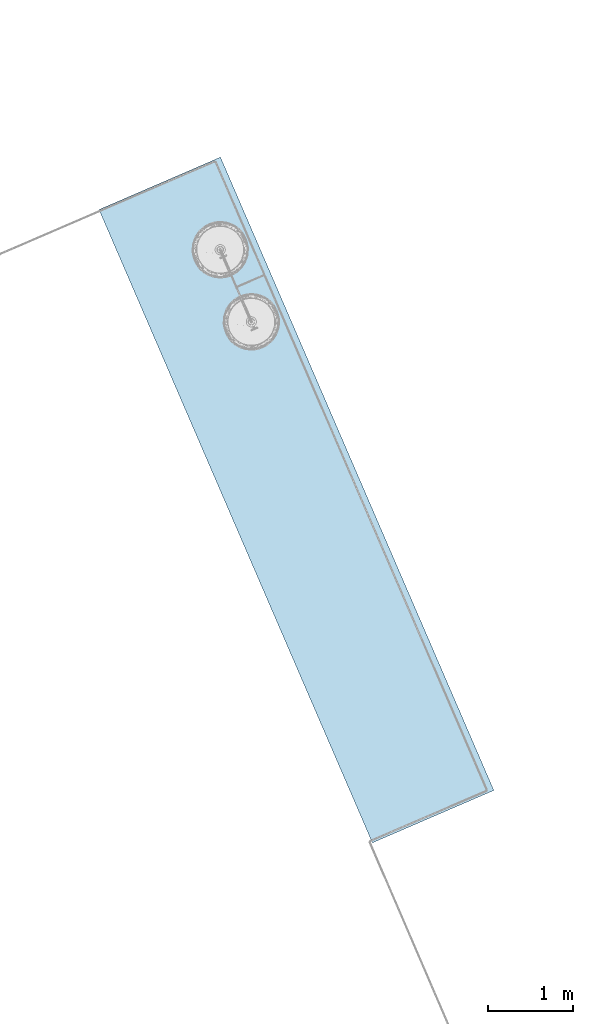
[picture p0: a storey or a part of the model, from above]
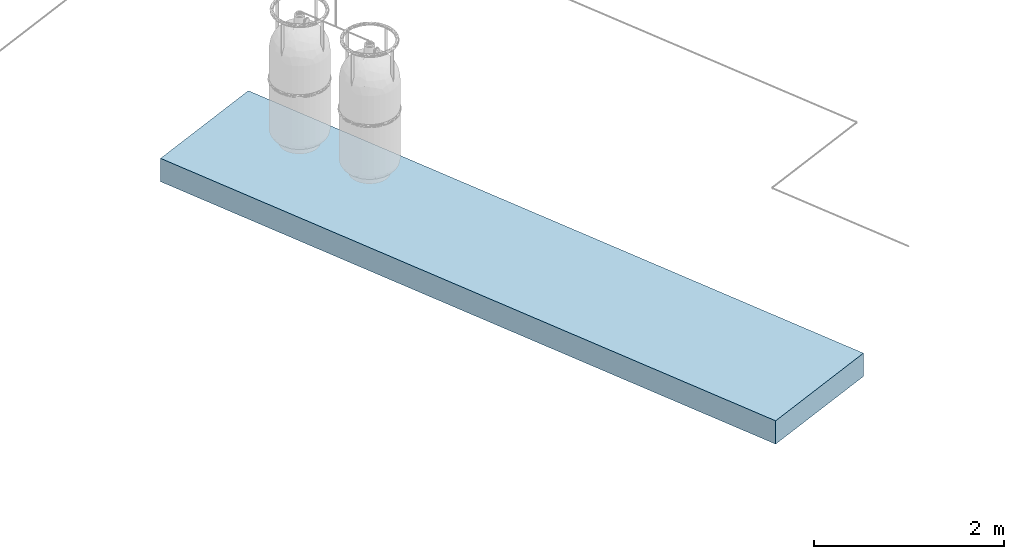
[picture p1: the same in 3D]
Properties of the parts of a building model (IFC4)

# File
Description: ViewDefinition [ReferenceView_V1.2], RevitIdentifiers [ContentGUID: 69321ab7-637c-4371-81d2-1dd4d23b8160, VersionGUID: b3f584a1-fc3a-4438-8aa8-f4ca3887ae56, NumberOfSaves: 3], CoordinateReference [CoordinateBase: Shared Coordinates, ProjectSite: Interno]
File name: C:\Users\Joaquin\Dropbox\BuildingProjects\2024 - Construcción Cesfam Coyhaique Con Sar Adosado\2_Modelos\all_models_2025-1-24_23.4.48\CCY_COOR-CCY_GAS_Enriched.ifc
Time: 2025-10-28T00:40:49-03:00
Written by: IfcOpenShell 0.8.3-post1
Made in: Bonsai 0.8.3-post1

# IfcProject, 2016_03
LongName: CESFAM Coyhaique; Phase: 2

# IfcSite, Default
RefLatitude: 42, 12, 46, 804504; RefLongitude: -71, -2, 0, -602416; RefElevation: 0 m
Pset_SiteCommon - Reference: Project Information
Other - Category: Project Information; Client Name: Servicio de Salud de Aysén; Project Address: Calle 2, s/n. Lote 1C.; Project Issue Date: Marzo 2017; Project Name: CESFAM Coyhaique; Project Number: 2016_03; Project Status: 2
Identity Data - Author: Astudillo y Aparicio Asociados Ltda.; Organization Description: Arquitectura e ingeniería integrada; Organization Name: Astudillo y Aparicio Asociados Ltda.

# IfcBuilding
Pset_BuildingCommon - Reference: Project Information; NumberOfStoreys: 2
Pset_BuildingElementProxyCommon - Reference: Project Information; IsExternal: no
Pset_BuildingSystemCommon - Reference: Project Information
Other - Category: Project Information; Client Name: Servicio de Salud de Aysén; Project Address: Calle 2, s/n. Lote 1C.; Project Issue Date: Marzo 2017; Project Name: CESFAM Coyhaique; Project Number: 2016_03; Project Status: 2
Identity Data - Author: Astudillo y Aparicio Asociados Ltda.; Organization Description: Arquitectura e ingeniería integrada; Organization Name: Astudillo y Aparicio Asociados Ltda.

# IfcBuildingStorey: Level:Extremo inicial 8 mm (2)
Other - Category: Levels; Family: Level; Family and Type: Level: Extremo inicial 8 mm; Type: Extremo inicial 8 mm; Type Id: 305
Dimensions - Computation Height: 0 m
Identity Data - Structural: no; Building Story: yes
Other(Type) - Category: Levels; Family Name: Level
Constraints(Type) - Elevation Base: Survey Point
Graphics(Type) - Color: 0; Line Pattern: Centro; Line Weight: 1; Symbol: M_Extremo inicial de nivel - Círculo; Symbol at End 1 Default: no; Symbol at End 2 Default: yes
Identity Data(Type) - Type Name: Extremo inicial 8 mm
Name | LongName = Name | Elevation (m) | Constraints, Elevation (m)
Nivel 1 | Nivel 1 | 0 | 317.15
Nivel 2 | Nivel 2 | 4.25 | 321.4

# IfcBurner: Mechero:Mechero (5)
Type - Material: <Unnamed>
Type - Other - Category: Mechanical Equipment; Family Name: Mechero
Type - Constraints - Default Elevation: 0 m
Type - Dimensions - Entrada: 0.013 m
Type - Identity Data - Type Name: Mechero
Classification: D20 (FEMAP58); Group: Otros 1
Pset_BuildingElementProxyCommon - IsExternal: no; Reference: Mechero:Mechero
Pset_EnvironmentalImpactIndicators - Reference: Mechero:Mechero
Qto_BuildingElementProxyQuantities - NetSurfaceArea: 0.51635 m2; NetVolume: 0.00811626 m3
Other - Family: Mechero; Family and Type: Mechero: Mechero; Type: Mechero; Type Id: 1006093
Constraints - Elevation from Level: 0.75 m; Offset from Host: 0.75 m
Dimensions - Area: 0.258175 m2; Volume: 0.00811626 m3
Mechanical - System Classification: Other; System Name: Otros 1
Phasing - Phase Created: Nueva construcción
AboveGround - AboveGround: yes
Name (Mechero:Mechero:...) | In | Level | Host | Mark
1006108 | Nivel 1 | Nivel 1 | Level : Nivel 1
1006902 | Nivel 1 | Nivel 1 | Level : Nivel 1 | 12
1006960 | Nivel 1 | Nivel 1 | Level : Nivel 1 | 13
1008166 | Nivel 2 | Nivel 2 | Level : Nivel 2 | 14
1008171 | Nivel 2 | Nivel 2 | Level : Nivel 2 | 15

# IfcDistributionPort (210)
Description: Flow; PredefinedType: PIPE
Name | FlowDirection | SystemType | Group
InPort_955634_1 | SINK | DOMESTICCOLDWATER
InPort_955634_2 | SINK | DOMESTICHOTWATER
InPort_955634_3 | SINK | SEWAGE
InPort_955636_1 | SINK | DOMESTICCOLDWATER
InPort_955636_2 | SINK | DOMESTICHOTWATER
InPort_955636_3 | SINK | SEWAGE
OutPort_996003_1 | SOURCE
Port_1001599_1 | SOURCEANDSINK
InPort_1008911_0 | SINK | USERDEFINED | Otros 2
OutPort_1001599_2 | SOURCE | USERDEFINED | Otros 2
InPort_1007986_1 | SINK | USERDEFINED | Otros 1
OutPort_1003499_1 | SOURCE | USERDEFINED | Otros 1
InPort_1007988_1 | SINK | USERDEFINED | Otros 1
OutPort_1004430_1 | SOURCE | USERDEFINED | Otros 1
InPort_1007066_2 | SINK | USERDEFINED | Otros 1
OutPort_1006108_1 | SOURCE | USERDEFINED | Otros 1
InPort_1007020_1 | SINK | USERDEFINED | Otros 1
OutPort_1006902_1 | SOURCE | USERDEFINED | Otros 1
InPort_1006984_1 | SINK | USERDEFINED | Otros 1
OutPort_1006960_1 | SOURCE | USERDEFINED | Otros 1
Port_1006974_0 | SOURCEANDSINK | USERDEFINED | Otros 1
Port_1006984_2 | SOURCEANDSINK | USERDEFINED | Otros 1
Port_1006974_1 | SOURCEANDSINK | USERDEFINED | Otros 1
Port_1007147_2 | SOURCEANDSINK | USERDEFINED | Otros 1
Port_1006987_0 | SOURCEANDSINK | USERDEFINED | Otros 1
Port_1007676_2 | SOURCEANDSINK | USERDEFINED | Otros 1
Port_1006987_1 | SOURCEANDSINK | USERDEFINED | Otros 1
Port_1007147_1 | SOURCEANDSINK | USERDEFINED | Otros 1
Port_1007012_0 | SOURCEANDSINK | USERDEFINED | Otros 1
Port_1007020_2 | SOURCEANDSINK | USERDEFINED | Otros 1
Port_1007012_1 | SOURCEANDSINK | USERDEFINED | Otros 1
Port_1007030_1 | SOURCEANDSINK | USERDEFINED | Otros 1
Port_1007022_0 | SOURCEANDSINK | USERDEFINED | Otros 1
Port_1007062_1 | SOURCEANDSINK | USERDEFINED | Otros 1
Port_1007022_1 | SOURCEANDSINK | USERDEFINED | Otros 1
Port_1008821_1 | SOURCEANDSINK | USERDEFINED | Otros 1
Port_1007030_2 | SOURCEANDSINK | USERDEFINED | Otros 1
Port_1007063_0 | SOURCEANDSINK | USERDEFINED | Otros 1
Port_1007050_0 | SOURCEANDSINK | USERDEFINED | Otros 1
Port_1007062_3 | SOURCEANDSINK | USERDEFINED | Otros 1
Port_1007050_1 | SOURCEANDSINK | USERDEFINED | Otros 1
Port_1007066_1 | SOURCEANDSINK | USERDEFINED | Otros 1
Port_1007062_2 | SOURCEANDSINK | USERDEFINED | Otros 1
Port_1007063_1 | SOURCEANDSINK | USERDEFINED | Otros 1
Port_1007094_0 | SOURCEANDSINK | USERDEFINED | Otros 1
Port_1008833_2 | SOURCEANDSINK | USERDEFINED | Otros 1
Port_1007094_1 | SOURCEANDSINK | USERDEFINED | Otros 1
Port_1007117_1 | SOURCEANDSINK | USERDEFINED | Otros 1
Port_1007111_0 | SOURCEANDSINK | USERDEFINED | Otros 1
Port_1008793_1 | SOURCEANDSINK | USERDEFINED | Otros 1
Port_1007111_1 | SOURCEANDSINK | USERDEFINED | Otros 1
Port_1008694_1 | SOURCEANDSINK | USERDEFINED | Otros 1
Port_1007117_2 | SOURCEANDSINK | USERDEFINED | Otros 1
Port_1008794_0 | SOURCEANDSINK | USERDEFINED | Otros 1
Port_1007164_0 | SOURCEANDSINK | USERDEFINED | Otros 1
Port_1007988_2 | SOURCEANDSINK | USERDEFINED | Otros 1
Port_1007164_1 | SOURCEANDSINK | USERDEFINED | Otros 1
Port_1007992_2 | SOURCEANDSINK | USERDEFINED | Otros 1
Port_1007174_0 | SOURCEANDSINK | USERDEFINED | Otros 1
Port_1007986_2 | SOURCEANDSINK | USERDEFINED | Otros 1
Port_1007174_1 | SOURCEANDSINK | USERDEFINED | Otros 1
Port_1007990_2 | SOURCEANDSINK | USERDEFINED | Otros 1
Port_1007210_0 | SOURCEANDSINK | USERDEFINED | Otros 1
Port_1008692_1 | SOURCEANDSINK | USERDEFINED | Otros 1
Port_1007210_1 | SOURCEANDSINK | USERDEFINED | Otros 1
Port_1008043_1 | SOURCEANDSINK | USERDEFINED | Otros 1
Port_1007220_0 | SOURCEANDSINK | USERDEFINED | Otros 1
Port_1007467_2 | SOURCEANDSINK | USERDEFINED | Otros 1
Port_1007220_1 | SOURCEANDSINK | USERDEFINED | Otros 1
Port_1008043_3 | SOURCEANDSINK | USERDEFINED | Otros 1
Port_1007234_0 | SOURCEANDSINK | USERDEFINED | Otros 1
Port_1007463_1 | SOURCEANDSINK | USERDEFINED | Otros 1
Port_1007234_1 | SOURCEANDSINK | USERDEFINED | Otros 1
Port_1007266_2 | SOURCEANDSINK | USERDEFINED | Otros 1
Port_1007260_1 | SOURCEANDSINK | USERDEFINED | Otros 1
Port_1007990_1 | SOURCEANDSINK | USERDEFINED | Otros 1
Port_1007260_2 | SOURCEANDSINK | USERDEFINED | Otros 1
Port_1007262_1 | SOURCEANDSINK | USERDEFINED | Otros 1
Port_1007262_2 | SOURCEANDSINK | USERDEFINED | Otros 1
Port_1007464_0 | SOURCEANDSINK | USERDEFINED | Otros 1
Port_1007264_1 | SOURCEANDSINK | USERDEFINED | Otros 1
Port_1007992_1 | SOURCEANDSINK | USERDEFINED | Otros 1
Port_1007264_2 | SOURCEANDSINK | USERDEFINED | Otros 1
Port_1007266_1 | SOURCEANDSINK | USERDEFINED | Otros 1
Port_1007461_0 | SOURCEANDSINK | USERDEFINED | Otros 1
Port_1007463_3 | SOURCEANDSINK | USERDEFINED | Otros 1
Port_1007461_1 | SOURCEANDSINK | USERDEFINED | Otros 1
Port_1007467_1 | SOURCEANDSINK | USERDEFINED | Otros 1
Port_1007463_2 | SOURCEANDSINK | USERDEFINED | Otros 1
Port_1007464_1 | SOURCEANDSINK | USERDEFINED | Otros 1
Port_1007626_0 | SOURCEANDSINK | USERDEFINED | Otros 1
Port_1007674_2 | SOURCEANDSINK | USERDEFINED | Otros 1
Port_1007626_1 | SOURCEANDSINK | USERDEFINED | Otros 1
Port_1008785_1 | SOURCEANDSINK | USERDEFINED | Otros 1
Port_1007649_0 | SOURCEANDSINK | USERDEFINED | Otros 1
Port_1007674_1 | SOURCEANDSINK | USERDEFINED | Otros 1
Port_1007649_1 | SOURCEANDSINK | USERDEFINED | Otros 1
Port_1007676_1 | SOURCEANDSINK | USERDEFINED | Otros 1
Port_1008043_2 | SOURCEANDSINK | USERDEFINED | Otros 1
Port_1008054_0 | SOURCEANDSINK | USERDEFINED | Otros 1
Port_1008054_1 | SOURCEANDSINK | USERDEFINED | Otros 1
Port_1008076_2 | SOURCEANDSINK | USERDEFINED | Otros 1
Port_1008068_0 | SOURCEANDSINK | USERDEFINED | Otros 1
Port_1008076_1 | SOURCEANDSINK | USERDEFINED | Otros 1
Port_1008068_1 | SOURCEANDSINK | USERDEFINED | Otros 1
Port_1008084_1 | SOURCEANDSINK | USERDEFINED | Otros 1
Port_1008078_0 | SOURCEANDSINK | USERDEFINED | Otros 1
Port_1008084_2 | SOURCEANDSINK | USERDEFINED | Otros 1
Port_1008078_1 | SOURCEANDSINK | USERDEFINED | Otros 1
Port_1008590_1 | SOURCEANDSINK | USERDEFINED | Otros 1
InPort_1008327_2 | SINK | USERDEFINED | Otros 1
OutPort_1008166_1 | SOURCE | USERDEFINED | Otros 1
InPort_1008290_1 | SINK | USERDEFINED | Otros 1
OutPort_1008171_1 | SOURCE | USERDEFINED | Otros 1
Port_1008210_0 | SOURCEANDSINK | USERDEFINED | Otros 1
Port_1008590_2 | SOURCEANDSINK | USERDEFINED | Otros 1
Port_1008210_1 | SOURCEANDSINK | USERDEFINED | Otros 1
Port_1008592_2 | SOURCEANDSINK | USERDEFINED | Otros 1
Port_1008239_0 | SOURCEANDSINK | USERDEFINED | Otros 1
Port_1008395_1 | SOURCEANDSINK | USERDEFINED | Otros 1
Port_1008239_1 | SOURCEANDSINK | USERDEFINED | Otros 1
Port_1008592_1 | SOURCEANDSINK | USERDEFINED | Otros 1
Port_1008275_0 | SOURCEANDSINK | USERDEFINED | Otros 1
Port_1008290_2 | SOURCEANDSINK | USERDEFINED | Otros 1
Port_1008275_1 | SOURCEANDSINK | USERDEFINED | Otros 1
Port_1008298_1 | SOURCEANDSINK | USERDEFINED | Otros 1
Port_1008292_0 | SOURCEANDSINK | USERDEFINED | Otros 1
Port_1008323_1 | SOURCEANDSINK | USERDEFINED | Otros 1
Port_1008292_1 | SOURCEANDSINK | USERDEFINED | Otros 1
Port_1008395_2 | SOURCEANDSINK | USERDEFINED | Otros 1
Port_1008298_2 | SOURCEANDSINK | USERDEFINED | Otros 1
Port_1008324_0 | SOURCEANDSINK | USERDEFINED | Otros 1
Port_1008311_0 | SOURCEANDSINK | USERDEFINED | Otros 1
Port_1008323_3 | SOURCEANDSINK | USERDEFINED | Otros 1
Port_1008311_1 | SOURCEANDSINK | USERDEFINED | Otros 1
Port_1008327_1 | SOURCEANDSINK | USERDEFINED | Otros 1
Port_1008323_2 | SOURCEANDSINK | USERDEFINED | Otros 1
Port_1008324_1 | SOURCEANDSINK | USERDEFINED | Otros 1
Port_1008690_0 | SOURCEANDSINK | USERDEFINED | Otros 1
Port_1008692_2 | SOURCEANDSINK | USERDEFINED | Otros 1
Port_1008690_1 | SOURCEANDSINK | USERDEFINED | Otros 1
Port_1008694_2 | SOURCEANDSINK | USERDEFINED | Otros 1
Port_1008774_0 | SOURCEANDSINK | USERDEFINED | Otros 1
Port_1008793_3 | SOURCEANDSINK | USERDEFINED | Otros 1
Port_1008774_1 | SOURCEANDSINK | USERDEFINED | Otros 1
Port_1008797_2 | SOURCEANDSINK | USERDEFINED | Otros 1
Port_1008783_0 | SOURCEANDSINK | USERDEFINED | Otros 1
Port_1008785_2 | SOURCEANDSINK | USERDEFINED | Otros 1
Port_1008783_1 | SOURCEANDSINK | USERDEFINED | Otros 1
Port_1008797_1 | SOURCEANDSINK | USERDEFINED | Otros 1
Port_1008793_2 | SOURCEANDSINK | USERDEFINED | Otros 1
Port_1008794_1 | SOURCEANDSINK | USERDEFINED | Otros 1
Port_1008808_0 | SOURCEANDSINK | USERDEFINED | Otros 1
Port_1008833_1 | SOURCEANDSINK | USERDEFINED | Otros 1
Port_1008808_1 | SOURCEANDSINK | USERDEFINED | Otros 1
Port_1008835_2 | SOURCEANDSINK | USERDEFINED | Otros 1
Port_1008819_0 | SOURCEANDSINK | USERDEFINED | Otros 1
Port_1008821_2 | SOURCEANDSINK | USERDEFINED | Otros 1
Port_1008819_1 | SOURCEANDSINK | USERDEFINED | Otros 1
Port_1008835_1 | SOURCEANDSINK | USERDEFINED | Otros 1
Port_1008885_1 | SOURCEANDSINK
InPort_1009899_0 | SINK | USERDEFINED | Otros 2
OutPort_1008885_2 | SOURCE | USERDEFINED | Otros 2
Port_1008899_0 | SOURCEANDSINK | USERDEFINED | Otros 2
Port_1008913_2 | SOURCEANDSINK | USERDEFINED | Otros 2
Port_1008899_1 | SOURCEANDSINK | USERDEFINED | Otros 2
Port_1008951_1 | SOURCEANDSINK | USERDEFINED | Otros 2
Port_1008911_1 | SOURCEANDSINK | USERDEFINED | Otros 2
Port_1008913_1 | SOURCEANDSINK | USERDEFINED | Otros 2
Port_1008951_2 | SOURCEANDSINK | USERDEFINED | Otros 2
Port_1009927_0 | SOURCEANDSINK | USERDEFINED | Otros 2
Port_1009399_0 | SOURCEANDSINK | USERDEFINED | Otros 2
Port_1009926_1 | SOURCEANDSINK | USERDEFINED | Otros 2
Port_1009399_1 | SOURCEANDSINK | USERDEFINED | Otros 2
Port_1009435_1 | SOURCEANDSINK | USERDEFINED | Otros 2
Port_1009425_0 | SOURCEANDSINK | USERDEFINED | Otros 2
Port_1009435_2 | SOURCEANDSINK | USERDEFINED | Otros 2
Port_1009425_1 | SOURCEANDSINK | USERDEFINED | Otros 2
Port_1009476_1 | SOURCEANDSINK | USERDEFINED | Otros 2
Port_1009437_0 | SOURCEANDSINK | USERDEFINED | Otros 2
Port_1009478_2 | SOURCEANDSINK | USERDEFINED | Otros 2
Port_1009437_1 | SOURCEANDSINK | USERDEFINED | Otros 2
Port_1009531_1 | SOURCEANDSINK | USERDEFINED | Otros 2
Port_1009474_0 | SOURCEANDSINK | USERDEFINED | Otros 2
Port_1009476_2 | SOURCEANDSINK | USERDEFINED | Otros 2
Port_1009474_1 | SOURCEANDSINK | USERDEFINED | Otros 2
Port_1009478_1 | SOURCEANDSINK | USERDEFINED | Otros 2
Port_1009482_0 | SOURCEANDSINK | USERDEFINED | Otros 2
Port_1009535_2 | SOURCEANDSINK | USERDEFINED | Otros 2
Port_1009482_1 | SOURCEANDSINK | USERDEFINED | Otros 2
Port_1009799_1 | SOURCEANDSINK | USERDEFINED | Otros 2
Port_1009529_0 | SOURCEANDSINK | USERDEFINED | Otros 2
Port_1009531_2 | SOURCEANDSINK | USERDEFINED | Otros 2
Port_1009529_1 | SOURCEANDSINK | USERDEFINED | Otros 2
Port_1009535_1 | SOURCEANDSINK | USERDEFINED | Otros 2
Port_1009539_0 | SOURCEANDSINK | USERDEFINED | Otros 2
Port_1009799_2 | SOURCEANDSINK | USERDEFINED | Otros 2
Port_1009539_1 | SOURCEANDSINK | USERDEFINED | Otros 2
Port_1009810_1 | SOURCEANDSINK | USERDEFINED | Otros 2
Port_1009802_0 | SOURCEANDSINK | USERDEFINED | Otros 2
Port_1009810_2 | SOURCEANDSINK | USERDEFINED | Otros 2
Port_1009802_1 | SOURCEANDSINK | USERDEFINED | Otros 2
Port_1009889_0 | SOURCEANDSINK | USERDEFINED | Otros 2
Port_1009926_3 | SOURCEANDSINK | USERDEFINED | Otros 2
Port_1009889_1 | SOURCEANDSINK | USERDEFINED | Otros 2
Port_1009930_2 | SOURCEANDSINK | USERDEFINED | Otros 2
Port_1009899_1 | SOURCEANDSINK | USERDEFINED | Otros 2
Port_1009930_1 | SOURCEANDSINK | USERDEFINED | Otros 2
Port_1009926_2 | SOURCEANDSINK | USERDEFINED | Otros 2
Port_1009927_1 | SOURCEANDSINK | USERDEFINED | Otros 2

# IfcDistributionSystem: Otros (2)
PredefinedType: USERDEFINED
Pset_DistributionSystemCommon - Reference: Piping System:Otros
Name
Otros 2
Otros 1

# IfcFlowTerminal: M_Fregadero - Isla - Simple:455 mm x 455 mm - Público (2)
In: Nivel 1
Type - Material: <Unnamed>
Type - Other - Category: Plumbing Fixtures; Family Name: M_Fregadero - Isla - Simple
Type - Constraints - Default Elevation: 0 m
Type - Dimensions - Anchura de fregadero: 0.455 m; Diámetro de agua caliente: 0.015 m; Diámetro de agua fría: 0.015 m; Diámetro de sanitario: 0.04 m; Longitud de fregadero: 0.455 m; Profundidad de fregadero: 0.203 m; Radio de agua caliente: 0.0075 m; Radio de agua fría: 0.0075 m; Radio de sanitario: 0.02 m
Type - Identity Data - OmniClass Number: 23.45.05.14.14; OmniClass Title: Sinks/Lavatories; Type Name: 455 mm x 455 mm - Público
Type - Mechanical - CWFU: 3; HWFU: 3; WFU: 2
Classification: D20 (FEMAP58)
Pset_EnvironmentalImpactIndicators - Reference: M_Fregadero - Isla - Simple:455 mm x 455 mm - Público
Other - Family: M_Fregadero - Isla - Simple; Family and Type: M_Fregadero - Isla - Simple: 455 mm x 455 mm - Público; Type: 455 mm x 455 mm - Público; Type Id: 921487
Constraints - Elevation from Level: 0 m
Dimensions - Area: 0.498697 m2; Volume: 0.00640577 m3
Mechanical - System Classification: Domestic Cold Water,Domestic Hot Water,Sanitary
Phasing - Phase Created: Nueva construcción
Plumbing - Presión de flujo: 55158 Pa
AboveGround - AboveGround: yes
Name (M_Fregadero - Isla - Simple:455 mm x 455 mm - Público:...) | Mark
955634 | 228
955636 | 230

# IfcGrid (2)
AboveGround - AboveGround: yes
Name | In
Default Grid | Nivel 1
Default Grid | Nivel 2

# IfcPipeFitting: M_Codo - Genérico:Norma (31)
Type - Material: <Unnamed>
Type - Other - Category: Pipe Fittings; Family Name: M_Codo - Genérico; Nombre de tabla de consulta: M_Pipe Fitting - Generic
Type - Constraints - Default Elevation: 0 m
Type - Identity Data - OmniClass Number: 23.60.30.11.14; OmniClass Title: Pipework Fittings; Type Name: Norma
Type - Mechanical - Loss Method: K Coefficient from Table; Connection Type: Generic; K Coefficient Table: Regular 45, 90 and 180 Elbow
Classification: D20 (FEMAP58)
Pset_EnvironmentalImpactIndicators - Reference: M_Codo - Genérico:Norma; sets with these values: 2
Other - Type: Norma; Family: M_Codo - Genérico; Family and Type: M_Codo - Genérico: Norma; Type Id: 133158
Dimensions - Ángulo: 90 deg
Graphics - Use Annotation Scale: yes
Mechanical - System Type: Otros; System Classification: Other
Phasing - Phase Created: Nueva construcción
Insulation - Insulation Thickness: 0 m
AboveGround - AboveGround: yes
Name (M_Codo - Genérico:Norma:...) | In | Radio central (m) = Centro a extremo (m) | Radio exterior de unión (m) | Level | Elevation from Level (m) | Diámetro exterior de unión (m) | Diámetro nominal (m) = Maximum Size (m) = Minimum Size (m) | Radio nominal (m) | Size | Tamaño de marca (m) | Volume (m3) | System Name = Group | Overall Size
1007030 | Nivel 1 | 0.0174625 | 0.0111125 | Nivel 1 | 0.8555 | 0.022225 | 0.02 | 0.01 | 0.020ø-0.020ø | 0.00889 | 0.0000106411 | Otros 1 | 20 mmø-20 mmø
1007117 | Nivel 1 | 0.0174625 | 0.0111125 | Nivel 1 | 3 | 0.022225 | 0.02 | 0.01 | 0.020ø-0.020ø | 0.00889 | 0.0000106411 | Otros 1 | 20 mmø-20 mmø
1007147 | Nivel 1 | 0.0174625 | 0.0111125 | Nivel 1 | 0.8555 | 0.022225 | 0.02 | 0.01 | 0.020ø-0.020ø | 0.00889 | 0.0000106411 | Otros 1 | 20 mmø-20 mmø
1007260 | Nivel 1 | 0.0144375 | 0.0080875 | Nivel 1 | 1.6819 | 0.016175 | 0.013 | 0.0065 | 0.013ø-0.013ø | 0.00647 | 0.00000465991 | Otros 1 | 13 mmø-13 mmø
1007264 | Nivel 1 | 0.0144375 | 0.0080875 | Nivel 1 | 1.6819 | 0.016175 | 0.013 | 0.0065 | 0.013ø-0.013ø | 0.00647 | 0.00000465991 | Otros 1 | 13 mmø-13 mmø
1007467 | Nivel 1 | 0.0174625 | 0.0111125 | Nivel 1 | 3 | 0.022225 | 0.02 | 0.01 | 0.020ø-0.020ø | 0.00889 | 0.0000106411 | Otros 1 | 20 mmø-20 mmø | Identity Data - Comments: GAS
1007674 | Nivel 1 | 0.0174625 | 0.0111125 | Nivel 1 | 0.8555 | 0.022225 | 0.02 | 0.01 | 0.020ø-0.020ø | 0.00889 | 0.0000106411 | Otros 1 | 20 mmø-20 mmø
1007676 | Nivel 1 | 0.0174625 | 0.0111125 | Nivel 1 | 0.8555 | 0.022225 | 0.02 | 0.01 | 0.020ø-0.020ø | 0.00889 | 0.0000106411 | Otros 1 | 20 mmø-20 mmø
1008076 | Nivel 1 | 0.0174625 | 0.0111125 | Nivel 1 | 3 | 0.022225 | 0.02 | 0.01 | 0.020ø-0.020ø | 0.00889 | 0.0000106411 | Otros 1 | 20 mmø-20 mmø
1008084 | Nivel 1 | 0.0174625 | 0.0111125 | Nivel 1 | 3 | 0.022225 | 0.02 | 0.01 | 0.020ø-0.020ø | 0.00889 | 0.0000106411 | Otros 1 | 20 mmø-20 mmø
1008298 | Nivel 2 | 0.0174625 | 0.0111125 | Nivel 2 | 0.8555 | 0.022225 | 0.02 | 0.01 | 0.020ø-0.020ø | 0.00889 | 0.0000106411 | Otros 1 | 20 mmø-20 mmø
1008395 | Nivel 1 | 0.0174625 | 0.0111125 | Nivel 1 | 5.1055 | 0.022225 | 0.02 | 0.01 | 0.020ø-0.020ø | 0.00889 | 0.0000106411 | Otros 1 | 20 mmø-20 mmø
1008590 | Nivel 1 | 0.0174625 | 0.0111125 | Nivel 1 | 3 | 0.022225 | 0.02 | 0.01 | 0.020ø-0.020ø | 0.00889 | 0.0000106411 | Otros 1 | 20 mmø-20 mmø
1008592 | Nivel 1 | 0.0174625 | 0.0111125 | Nivel 1 | 3 | 0.022225 | 0.02 | 0.01 | 0.020ø-0.020ø | 0.00889 | 0.0000106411 | Otros 1 | 20 mmø-20 mmø
1008692 | Nivel 1 | 0.0174625 | 0.0111125 | Nivel 1 | 3 | 0.022225 | 0.02 | 0.01 | 0.020ø-0.020ø | 0.00889 | 0.0000106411 | Otros 1 | 20 mmø-20 mmø | Identity Data - Comments: GAS
1008694 | Nivel 1 | 0.0174625 | 0.0111125 | Nivel 1 | 3 | 0.022225 | 0.02 | 0.01 | 0.020ø-0.020ø | 0.00889 | 0.0000106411 | Otros 1 | 20 mmø-20 mmø | Identity Data - Comments: GAS
1008785 | Nivel 1 | 0.0174625 | 0.0111125 | Nivel 1 | 0.8555 | 0.022225 | 0.02 | 0.01 | 0.020ø-0.020ø | 0.00889 | 0.0000106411 | Otros 1 | 20 mmø-20 mmø
1008797 | Nivel 1 | 0.0174625 | 0.0111125 | Nivel 1 | 3 | 0.022225 | 0.02 | 0.01 | 0.020ø-0.020ø | 0.00889 | 0.0000106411 | Otros 1 | 20 mmø-20 mmø
1008821 | Nivel 1 | 0.0174625 | 0.0111125 | Nivel 1 | 0.8555 | 0.022225 | 0.02 | 0.01 | 0.020ø-0.020ø | 0.00889 | 0.0000106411 | Otros 1 | 20 mmø-20 mmø
1008833 | Nivel 1 | 0.0174625 | 0.0111125 | Nivel 1 | 3 | 0.022225 | 0.02 | 0.01 | 0.020ø-0.020ø | 0.00889 | 0.0000106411 | Otros 1 | 20 mmø-20 mmø
1008835 | Nivel 1 | 0.0174625 | 0.0111125 | Nivel 1 | 3 | 0.022225 | 0.02 | 0.01 | 0.020ø-0.020ø | 0.00889 | 0.0000106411 | Otros 1 | 20 mmø-20 mmø | Mechanical - Flow - Pressure Drop: 0 Pa
1008913 | Nivel 1 | 0.0206375 | 0.0142875 | Nivel 1 | -0.44 | 0.028575 | 0.025 | 0.0125 | 0.025ø-0.025ø | 0.01143 | 0.0000207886 | Otros 2 | 25 mmø-25 mmø
1008951 | Nivel 1 | 0.0206375 | 0.0142875 | Nivel 1 | -0.44 | 0.028575 | 0.025 | 0.0125 | 0.025ø-0.025ø | 0.01143 | 0.0000207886 | Otros 2 | 25 mmø-25 mmø
1009435 | Nivel 1 | 0.0206375 | 0.0142875 | Nivel 1 | -0.44 | 0.028575 | 0.025 | 0.0125 | 0.025ø-0.025ø | 0.01143 | 0.0000207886 | Otros 2 | 25 mmø-25 mmø
1009476 | Nivel 1 | 0.0206375 | 0.0142875 | Nivel 1 | -0.44 | 0.028575 | 0.025 | 0.0125 | 0.025ø-0.025ø | 0.01143 | 0.0000207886 | Otros 2 | 25 mmø-25 mmø
1009478 | Nivel 1 | 0.0206375 | 0.0142875 | Nivel 1 | 0.4 | 0.028575 | 0.025 | 0.0125 | 0.025ø-0.025ø | 0.01143 | 0.0000207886 | Otros 2 | 25 mmø-25 mmø
1009531 | Nivel 1 | 0.0206375 | 0.0142875 | Nivel 1 | 0.4 | 0.028575 | 0.025 | 0.0125 | 0.025ø-0.025ø | 0.01143 | 0.0000207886 | Otros 2 | 25 mmø-25 mmø
1009535 | Nivel 1 | 0.0206375 | 0.0142875 | Nivel 1 | 1.8 | 0.028575 | 0.025 | 0.0125 | 0.025ø-0.025ø | 0.01143 | 0.0000207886 | Otros 2 | 25 mmø-25 mmø
1009799 | Nivel 1 | 0.0206375 | 0.0142875 | Nivel 1 | 1.8 | 0.028575 | 0.025 | 0.0125 | 0.025ø-0.025ø | 0.01143 | 0.0000207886 | Otros 2 | 25 mmø-25 mmø
1009810 | Nivel 1 | 0.0206375 | 0.0142875 | Nivel 1 | 3.84207 | 0.028575 | 0.025 | 0.0125 | 0.025ø-0.025ø | 0.01143 | 0.0000207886 | Otros 2 | 25 mmø-25 mmø
1009930 | Nivel 1 | 0.0206375 | 0.0142875 | Nivel 1 | -0.44 | 0.028575 | 0.025 | 0.0125 | 0.025ø-0.025ø | 0.01143 | 0.0000207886 | Otros 2 | 25 mmø-25 mmø

# IfcPipeFitting: M_Te - Genérica:Norma (6)
Type - Material: <Unnamed>
Type - Other - Category: Pipe Fittings; Family Name: M_Te - Genérica; Nombre de tabla de consulta: M_Pipe Fitting - Generic
Type - Constraints - Default Elevation: 0 m
Type - Identity Data - OmniClass Number: 23.60.30.11.14; OmniClass Title: Pipework Fittings; Type Name: Norma
Type - Mechanical - Loss Method: K Coefficient from Table; Connection Type: Generic; K Coefficient Table: Tee
Classification: D20 (FEMAP58)
Pset_EnvironmentalImpactIndicators - Reference: M_Te - Genérica:Norma; sets with these values: 2
Other - Type: Norma; Ángulo 1: 90 deg; Family: M_Te - Genérica; Family and Type: M_Te - Genérica: Norma; Type Id: 130550
Dimensions - Ángulo: 90 deg
Graphics - Use Annotation Scale: yes
Mechanical - System Type: Otros; System Classification: Other
Phasing - Phase Created: Nueva construcción
Insulation - Insulation Thickness: 0 m
AboveGround - AboveGround: yes
Name (M_Te - Genérica:Norma:...) | In | Centro a etiqueta de extremo (m) = Centro a extremo (m) | Radio exterior de unión (m) | Level | Elevation from Level (m) | Diámetro exterior de unión (m) | Diámetro nominal (m) = Maximum Size (m) = Minimum Size (m) | Radio nominal (m) | Size | Tamaño de marca (m) | Volume (m3) | System Name = Group | Overall Size
1007062 | Nivel 1 | 0.0238125 | 0.0111125 | Nivel 1 | 0.8555 | 0.022225 | 0.02 | 0.01 | 0.020ø-0.020ø-0.020ø | 0.00889 | 0.0000240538 | Otros 1 | 20 mmø-20 mmø-20 mmø
1007463 | Nivel 1 | 0.0238125 | 0.0111125 | Nivel 1 | 1.6819 | 0.022225 | 0.02 | 0.01 | 0.020ø-0.020ø-0.020ø | 0.00889 | 0.0000240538 | Otros 1 | 20 mmø-20 mmø-20 mmø | Identity Data - Comments: GAS
1008043 | Nivel 1 | 0.0238125 | 0.0111125 | Nivel 1 | 3 | 0.022225 | 0.02 | 0.01 | 0.020ø-0.020ø-0.020ø | 0.00889 | 0.0000240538 | Otros 1 | 20 mmø-20 mmø-20 mmø
1008323 | Nivel 2 | 0.0238125 | 0.0111125 | Nivel 2 | 0.8555 | 0.022225 | 0.02 | 0.01 | 0.020ø-0.020ø-0.020ø | 0.00889 | 0.0000240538 | Otros 1 | 20 mmø-20 mmø-20 mmø
1008793 | Nivel 1 | 0.0238125 | 0.0111125 | Nivel 1 | 3 | 0.022225 | 0.02 | 0.01 | 0.020ø-0.020ø-0.020ø | 0.00889 | 0.0000240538 | Otros 1 | 20 mmø-20 mmø-20 mmø
1009926 | Nivel 1 | 0.0269875 | 0.0142875 | Nivel 1 | -0.44 | 0.028575 | 0.025 | 0.0125 | 0.025ø-0.025ø-0.025ø | 0.01143 | 0.0000441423 | Otros 2 | 25 mmø-25 mmø-25 mmø

# IfcPipeFitting: M_Transición - Genérica:Norma (11)
Type - Material: <Unnamed>
Type - Other - Category: Pipe Fittings; Family Name: M_Transición - Genérica; Nombre de tabla de consulta: M_Pipe Fitting - Generic
Type - Constraints - Default Elevation: 0 m
Type - Identity Data - OmniClass Number: 23.60.30.11.14; OmniClass Title: Pipework Fittings; Type Name: Norma
Type - Mechanical - Connection Type: Generic; K Coefficient Table: Reducer/Coupling/Union/Increaser; Loss Method: K Coefficient from Table
Classification: D20 (FEMAP58); Group: Otros 1
Pset_EnvironmentalImpactIndicators - Reference: M_Transición - Genérica:Norma; sets with these values: 2
Other - Desfase de anchura: 32.8084 m; Diámetro exterior de unión máx. 12: 0.022225 m; Family: M_Transición - Genérica; Family and Type: M_Transición - Genérica: Norma; Type: Norma; Type Id: 194831; Visibilidad 1: no
Dimensions - Longitud: 0.00555625 m; Maximum Size: 0.02 m; Minimum Size: 0.013 m; Size: 0.020ø-0.013ø
Graphics - Use Annotation Scale: yes
Mechanical - System Type: Otros; System Classification: Other; System Name: Otros 1
Phasing - Phase Created: Nueva construcción
Insulation - Insulation Thickness: 0 m; Overall Size: 20 mmø-13 mmø
AboveGround - AboveGround: yes
Name (M_Transición - Genérica:Norma:...) | In | Desfase de altura (m) | Radio exterior de unión 1 (m) | Radio exterior de unión 2 (m) | Visibilidad 2 | Visibilidad 3 | Level | Elevation from Level (m) | Area (m2) | Diámetro exterior de unión 1 (m) | Diámetro exterior de unión 2 (m) | Diámetro nominal 1 (m) | Diámetro nominal 2 (m) | OffsetHeight | OffsetWidth | Radio nominal 1 (m) | Radio nominal 2 (m) | Tamaño de marca 1 (m) | Tamaño de marca 2 (m) | Volume (m3)
1006984 | Nivel 1 | 3.04796 | 0.0080875 | 0.0111125 | no | yes | Nivel 1 | 0.85554 | 0.000541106 | 0.016175 | 0.022225 | 0.013 | 0.02 | 6.4597 | 6.5 | 0.0065 | 0.01 | 0.00647 | 0.00889 | 0.0000016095
1007020 | Nivel 1 | 3.04796 | 0.0080875 | 0.0111125 | no | yes | Nivel 1 | 0.85554 | 0.000541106 | 0.016175 | 0.022225 | 0.013 | 0.02 | 6.4597 | 6.5 | 0.0065 | 0.01 | 0.00647 | 0.00889 | 0.0000016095
1007066 | Nivel 1 | 3.04804 | 0.0111125 | 0.0080875 | yes | no | Nivel 1 | 0.8555 | 0.000541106 | 0.022225 | 0.016175 | 0.02 | 0.013 | 10.0403 | 10 | 0.01 | 0.0065 | 0.00889 | 0.00647 | 0.0000015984
1007262 | Nivel 1 | 32.8084 | 0.0080875 | 0.0111125 | no | yes | Nivel 1 | 1.6819 | 0.000540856 | 0.016175 | 0.022225 | 0.013 | 0.02 | 6.5 | 6.5 | 0.0065 | 0.01 | 0.00647 | 0.00889 | 0.0000016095
1007266 | Nivel 1 | 32.8084 | 0.0080875 | 0.0111125 | no | yes | Nivel 1 | 1.6819 | 0.000540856 | 0.016175 | 0.022225 | 0.013 | 0.02 | 6.5 | 6.5 | 0.0065 | 0.01 | 0.00647 | 0.00889 | 0.0000016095
1007986 | Nivel 1 | 32.8084 | 0.0080875 | 0.0111125 | no | yes | Nivel 1 | 1.639 | 0.000540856 | 0.016175 | 0.022225 | 0.013 | 0.02 | 6.5 | 6.5 | 0.0065 | 0.01 | 0.00647 | 0.00889 | 0.0000016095
1007988 | Nivel 1 | 32.8084 | 0.0080875 | 0.0111125 | no | yes | Nivel 1 | 1.639 | 0.000540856 | 0.016175 | 0.022225 | 0.013 | 0.02 | 6.5 | 6.5 | 0.0065 | 0.01 | 0.00647 | 0.00889 | 0.0000016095
1007990 | Nivel 1 | 32.8084 | 0.0080875 | 0.0111125 | no | yes | Nivel 1 | 1.66746 | 0.000540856 | 0.016175 | 0.022225 | 0.013 | 0.02 | 6.5 | 6.5 | 0.0065 | 0.01 | 0.00647 | 0.00889 | 0.0000016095
1007992 | Nivel 1 | 32.8084 | 0.0080875 | 0.0111125 | no | yes | Nivel 1 | 1.66746 | 0.000540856 | 0.016175 | 0.022225 | 0.013 | 0.02 | 6.5 | 6.5 | 0.0065 | 0.01 | 0.00647 | 0.00889 | 0.0000016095
1008290 | Nivel 2 | 3.04796 | 0.0080875 | 0.0111125 | no | yes | Nivel 2 | 0.85554 | 0.000541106 | 0.016175 | 0.022225 | 0.013 | 0.02 | 6.4597 | 6.5 | 0.0065 | 0.01 | 0.00647 | 0.00889 | 0.0000016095
1008327 | Nivel 2 | 3.04804 | 0.0111125 | 0.0080875 | yes | no | Nivel 2 | 0.8555 | 0.000541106 | 0.022225 | 0.016175 | 0.02 | 0.013 | 10.0403 | 10 | 0.01 | 0.0065 | 0.00889 | 0.00647 | 0.0000015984

# IfcPipeSegment: Pipe Types:GAS (44)
Type - Other - Category: Pipes; Family Name: Pipe Types
Type - Identity Data - Type Name: GAS
Classification: D20 (FEMAP58); Material: Cobre
Pset_EnvironmentalImpactIndicators - Reference: Pipe Types:GAS; sets with these values: 2
Other - Family: Pipe Types; Family and Type: Pipe Types: GAS; Type: GAS; Type Id: 1007963
Constraints - Horizontal Justification: Center; Vertical Justification: Middle
Dimensions - Wall Thickness: 0 m
Mechanical - Connection Type: Generic; Material: Cobre; Pipe Segment: Cobre - A; Roughness: 0.00000254 m; Schedule/Type: A; System Classification: Other; System Type: Otros
Phasing - Phase Created: Nueva construcción
Insulation - Insulation Thickness: 0 m
AboveGround - AboveGround: yes
Name (Pipe Types:GAS:...) | In | InvertElevation (m) = Invert Elevation (m) | Pset_FlowSegmentDiameter, Diameter (m) = Inside Diameter (m) = Outside Diameter (m) = Mechanical, Diameter (m) | Qto_PipeSegmentBaseQuantities, Length (m) = Dimensions, Length (m) | GrossCrossSectionArea (m2) = NetCrossSectionArea (m2) | OuterSurfaceArea (m2) = Area (m2) | End Middle Elevation (m) | Lower End Bottom Elevation (m) = Lower End Invert Elevation (m) = Lower End Bottom of Insulation Elevation (m) | Lower End Centerline Elevation (m) | Lower End Obvert Elevation (m) = Lower End Top Elevation (m) = Lower End Top of Insulation Elevation (m) | Middle Elevation (m) = Start Middle Elevation (m) | Reference Level | Slope | Upper End Bottom Elevation (m) = Upper End Invert Elevation (m) = Upper End Bottom of Insulation Elevation (m) | Upper End Centerline Elevation (m) | Upper End Obvert Elevation (m) = Upper End Top Elevation (m) = Upper End Top of Insulation Elevation (m) | Size | System Name = Group | Relative Roughness | Section | Overall Size
1006974 | Nivel 1 | 0.8455 | 0.02 | 0.136981 | 0.000314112 | 0.00860679 | 0.8555 | 0.8455 | 0.8555 | 0.8655 | 0.8555 | Nivel 1 | 0 | 0.8455 | 0.8555 | 0.8655 | 0.020ø | Otros 1 | 0.000127 | 2 | 20 mmø | Identity Data - Comments: GAS
1006987 | Nivel 1 | 0.8455 | 0.02 | 0.817196 | 0.000314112 | 0.0513459 | 0.8555 | 0.8455 | 0.8555 | 0.8655 | 0.8555 | Nivel 1 | 0 | 0.8455 | 0.8555 | 0.8655 | 0.020ø | Otros 1 | 0.000127 | 2 | 20 mmø | Identity Data - Comments: GAS
1007012 | Nivel 1 | 0.8455 | 0.02 | 0.156981 | 0.000314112 | 0.00986342 | 0.8555 | 0.8455 | 0.8555 | 0.8655 | 0.8555 | Nivel 1 | 0 | 0.8455 | 0.8555 | 0.8655 | 0.020ø | Otros 1 | 0.000127 | 7 | 20 mmø | Identity Data - Comments: GAS
1007022 | Nivel 1 | 0.8455 | 0.02 | 0.161263 | 0.000314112 | 0.0101324 | 0.8555 | 0.8455 | 0.8555 | 0.8655 | 0.8555 | Nivel 1 | 0 | 0.8455 | 0.8555 | 0.8655 | 0.020ø | Otros 1 | 0.000127 | 32 | 20 mmø | Identity Data - Comments: GAS
1007050 | Nivel 1 | 0.8455 | 0.02 | 0.150631 | 0.000314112 | 0.00946444 | 0.8555 | 0.8455 | 0.8555 | 0.8655 | 0.8555 | Nivel 1 | 0 | 0.8455 | 0.8555 | 0.8655 | 0.020ø | Otros 1 | 0.000127 | 4 | 20 mmø | Identity Data - Comments: GAS
1007063 | Nivel 1 | 0.8455 | 0.02 | 0.558725 | 0.000314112 | 0.0351057 | 0.8555 | 0.8455 | 0.8555 | 0.8655 | 0.8555 | Nivel 1 | 0 | 0.8455 | 0.8555 | 0.8655 | 0.020ø | Otros 1 | 0.000127 | 7 | 20 mmø | Identity Data - Comments: GAS
1007094 | Nivel 1 | 2.99 | 0.02 | 2.44254 | 0.000314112 | 0.153469 | 3 | 2.99 | 3 | 3.01 | 3 | Nivel 1 | 0 | 2.99 | 3 | 3.01 | 0.020ø | Otros 1 | 0.000127 | 32 | 20 mmø | Identity Data - Comments: GAS
1007111 | Nivel 1 | 2.99 | 0.02 | 5.45676 | 0.000314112 | 0.342859 | 3 | 2.99 | 3 | 3.01 | 3 | Nivel 1 | 0 | 2.99 | 3 | 3.01 | 0.020ø | Otros 1 | 0.000127 | 31 | 20 mmø | Identity Data - Comments: GAS
1007164 | Nivel 1 | 1.64456 | 0.02 | 0.0173487 | 0.000314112 | 0.00109005 | 1.66191 | 1.64456 | 1.64456 | 1.64456 | 1.64456 | Nivel 1 |  | 1.66191 | 1.66191 | 1.66191 | 0.020ø | Otros 1 | 0.000127 | 20 | 20 mmø
1007174 | Nivel 1 | 1.64456 | 0.02 | 0.0173487 | 0.000314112 | 0.00109005 | 1.66191 | 1.64456 | 1.64456 | 1.64456 | 1.64456 | Nivel 1 |  | 1.66191 | 1.66191 | 1.66191 | 0.020ø | Otros 1 | 0.000127 | 18 | 20 mmø | Identity Data - Comments: GAS
1007210 | Nivel 1 | 2.99 | 0.02 | 1.41128 | 0.000314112 | 0.0886732 | 3 | 2.99 | 3 | 3.01 | 3 | Nivel 1 | 0 | 2.99 | 3 | 3.01 | 0.020ø | Otros 1 | 0.000127 | 31 | 20 mmø | Identity Data - Comments: GAS
1007220 | Nivel 1 | 2.99 | 0.02 | 0.317248 | 0.000314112 | 0.0199333 | 3 | 2.99 | 3 | 3.01 | 3 | Nivel 1 | 0 | 2.99 | 3 | 3.01 | 0.020ø | Otros 1 | 0.000127 | 14 | 20 mmø | Identity Data - Comments: GAS
1007234 | Nivel 1 | 1.6719 | 0.02 | 0.399099 | 0.000314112 | 0.0250761 | 1.6819 | 1.6719 | 1.6819 | 1.6919 | 1.6819 | Nivel 1 | 0 | 1.6719 | 1.6819 | 1.6919 | 0.020ø | Otros 1 | 0.000127 | 15 | 20 mmø
1007461 | Nivel 1 | 1.70571 | 0.02 | 1.27682 | 0.000314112 | 0.0802253 | 2.98254 | 1.70571 | 1.70571 | 1.70571 | 1.70571 | Nivel 1 |  | 2.98254 | 2.98254 | 2.98254 | 0.020ø | Otros 1 | 0.000127 | 14 | 20 mmø | Identity Data - Comments: GAS
1007464 | Nivel 1 | 1.6719 | 0.02 | 0.433289 | 0.000314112 | 0.0272243 | 1.6819 | 1.6719 | 1.6819 | 1.6919 | 1.6819 | Nivel 1 | 0 | 1.6719 | 1.6819 | 1.6919 | 0.020ø | Otros 1 | 0.000127 | 13 | 20 mmø | Identity Data - Comments: GAS
1007626 | Nivel 1 | 0.8455 | 0.02 | 0.145075 | 0.000314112 | 0.00911533 | 0.8555 | 0.8455 | 0.8555 | 0.8655 | 0.8555 | Nivel 1 | 0 | 0.8455 | 0.8555 | 0.8655 | 0.020ø | Otros 1 | 0.000127 | 2 | 20 mmø | Identity Data - Comments: GAS
1007649 | Nivel 1 | 0.8455 | 0.02 | 0.0936302 | 0.000314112 | 0.00588296 | 0.8555 | 0.8455 | 0.8555 | 0.8655 | 0.8555 | Nivel 1 | 0 | 0.8455 | 0.8555 | 0.8655 | 0.020ø | Otros 1 | 0.000127 | 2 | 20 mmø | Identity Data - Comments: GAS
1008054 | Nivel 1 | 2.99 | 0.02 | 6.53744 | 0.000314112 | 0.410759 | 3 | 2.99 | 3 | 3.01 | 3 | Nivel 1 | 0 | 2.99 | 3 | 3.01 | 0.020ø | Otros 1 | 0.000127 | 27 | 20 mmø
1008068 | Nivel 1 | 2.99 | 0.02 | 1.46787 | 0.000314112 | 0.0922288 | 3 | 2.99 | 3 | 3.01 | 3 | Nivel 1 | 0 | 2.99 | 3 | 3.01 | 0.020ø | Otros 1 | 0.000127 | 27 | 20 mmø
1008078 | Nivel 1 | 2.99 | 0.02 | 6.23654 | 0.000314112 | 0.391853 | 3 | 2.99 | 3 | 3.01 | 3 | Nivel 1 | 0 | 2.99 | 3 | 3.01 | 0.020ø | Otros 1 | 0.000127 | 27 | 20 mmø
1008210 | Nivel 1 | 2.99 | 0.02 | 0.473598 | 0.000314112 | 0.0297571 | 3 | 2.99 | 3 | 3.01 | 3 | Nivel 1 | 0 | 2.99 | 3 | 3.01 | 0.020ø | Otros 1 | 0.000127 | 27 | 20 mmø
1008239 | Nivel 1 | 3.01746 | 0.02 | 2.07058 | 0.000314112 | 0.130098 | 3.01746 | 3.01746 | 3.01746 | 3.01746 | 5.08804 | Nivel 1 |  | 5.08804 | 5.08804 | 5.08804 | 0.020ø | Otros 1 | 0.000127 | 27 | 20 mmø
1008275 | Nivel 2 | 5.0955 | 0.02 | 0.0486255 | 0.000314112 | 0.00305523 | 0.8555 | 0.8455 | 0.8555 | 0.8655 | 0.8555 | Nivel 2 | 0 | 0.8455 | 0.8555 | 0.8655 | 0.020ø | Otros 1 | 0.000127 | 23 | 20 mmø
1008292 | Nivel 2 | 5.0955 | 0.02 | 0.315322 | 0.000314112 | 0.0198123 | 0.8555 | 0.8455 | 0.8555 | 0.8655 | 0.8555 | Nivel 2 | 0 | 0.8455 | 0.8555 | 0.8655 | 0.020ø | Otros 1 | 0.000127 | 27 | 20 mmø
1008311 | Nivel 2 | 5.0955 | 0.02 | 0.0422755 | 0.000314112 | 0.00265625 | 0.8555 | 0.8455 | 0.8555 | 0.8655 | 0.8555 | Nivel 2 | 0 | 0.8455 | 0.8555 | 0.8655 | 0.020ø | Otros 1 | 0.000127 | 25 | 20 mmø
1008324 | Nivel 2 | 5.0955 | 0.02 | 0.48896 | 0.000314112 | 0.0307223 | 0.8555 | 0.8455 | 0.8555 | 0.8655 | 0.8555 | Nivel 2 | 0 | 0.8455 | 0.8555 | 0.8655 | 0.020ø | Otros 1 | 0.000127 | 23 | 20 mmø
1008774 | Nivel 1 | 2.99 | 0.02 | 0.497747 | 0.000314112 | 0.0312743 | 3 | 2.99 | 3 | 3.01 | 3 | Nivel 1 | 0 | 2.99 | 3 | 3.01 | 0.020ø | Otros 1 | 0.000127 | 2 | 20 mmø
1008783 | Nivel 1 | 0.872962 | 0.02 | 2.10958 | 0.000314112 | 0.132549 | 2.98254 | 0.872962 | 0.872962 | 0.872962 | 0.872962 | Nivel 1 |  | 2.98254 | 2.98254 | 2.98254 | 0.020ø | Otros 1 | 0.000127 | 2 | 20 mmø
1008794 | Nivel 1 | 2.99 | 0.02 | 6.21813 | 0.000314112 | 0.390697 | 3 | 2.99 | 3 | 3.01 | 3 | Nivel 1 | 0 | 2.99 | 3 | 3.01 | 0.020ø | Otros 1 | 0.000127 | 32 | 20 mmø | Identity Data - Comments: GAS
1008808 | Nivel 1 | 2.99 | 0.02 | 0.275075 | 0.000314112 | 0.0172835 | 3 | 2.99 | 3 | 3.01 | 3 | Nivel 1 | 0 | 2.99 | 3 | 3.01 | 0.020ø | Otros 1 | 0.000127 | 32 | 20 mmø
1008819 | Nivel 1 | 0.872962 | 0.02 | 2.10958 | 0.000314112 | 0.132549 | 2.98254 | 0.872962 | 0.872962 | 0.872962 | 0.872962 | Nivel 1 |  | 2.98254 | 2.98254 | 2.98254 | 0.020ø | Otros 1 | 0.000127 | 32 | 20 mmø
1008899 | Nivel 1 | -0.4525 | 0.025 | 4.75873 | 0.0004908 | 0.373749 | -0.44 | -0.4525 | -0.44 | -0.4275 | -0.44 | Nivel 1 | 0 | -0.4525 | -0.44 | -0.4275 | 0.025ø | Otros 2 | 0.0001016 | 2 | 25 mmø
1008911 | Nivel 1 | -0.549341 | 0.025 | 0.088703 | 0.0004908 | 0.00696672 | -0.460638 | -0.549341 | -0.549341 | -0.549341 | -0.549341 | Nivel 1 |  | -0.460638 | -0.460638 | -0.460638 | 0.025ø | Otros 2 | 0.0001016 | 2 | 25 mmø
1009399 | Nivel 1 | -0.4525 | 0.025 | 27.0013 | 0.0004908 | 2.12068 | -0.44 | -0.4525 | -0.44 | -0.4275 | -0.44 | Nivel 1 | 0 | -0.4525 | -0.44 | -0.4275 | 0.025ø | Otros 2 | 0.0001016 | 1 | 25 mmø
1009425 | Nivel 1 | -0.4525 | 0.025 | 0.495905 | 0.0004908 | 0.0389483 | -0.44 | -0.4525 | -0.44 | -0.4275 | -0.44 | Nivel 1 | 0 | -0.4525 | -0.44 | -0.4275 | 0.025ø | Otros 2 | 0.0001016 | 1 | 25 mmø
1009437 | Nivel 1 | 0.3875 | 0.025 | 0.358725 | 0.0004908 | 0.0281742 | 0.4 | 0.3875 | 0.4 | 0.4125 | 0.4 | Nivel 1 | 0 | 0.3875 | 0.4 | 0.4125 | 0.025ø | Otros 2 | 0.0001016 | 1 | 25 mmø
1009474 | Nivel 1 | -0.419362 | 0.025 | 0.798725 | 0.0004908 | 0.0627317 | 0.379363 | -0.419362 | -0.419362 | -0.419362 | -0.419362 | Nivel 1 |  | 0.379362 | 0.379363 | 0.379362 | 0.025ø | Otros 2 | 0.0001016 | 1 | 25 mmø
1009482 | Nivel 1 | 1.7875 | 0.025 | 0.278725 | 0.0004908 | 0.021891 | 1.8 | 1.7875 | 1.8 | 1.8125 | 1.8 | Nivel 1 | 0 | 1.7875 | 1.8 | 1.8125 | 0.025ø | Otros 2 | 0.0001016 | 1 | 25 mmø
1009529 | Nivel 1 | 0.420637 | 0.025 | 1.35872 | 0.0004908 | 0.106714 | 1.77936 | 0.420637 | 0.420637 | 0.420637 | 0.420637 | Nivel 1 |  | 1.77936 | 1.77936 | 1.77936 | 0.025ø | Otros 2 | 0.0001016 | 1 | 25 mmø
1009539 | Nivel 1 | 1.82064 | 0.025 | 2.00079 | 0.0004908 | 0.157142 | 3.82143 | 1.82064 | 1.82064 | 1.82064 | 1.82064 | Nivel 1 |  | 3.82143 | 3.82143 | 3.82143 | 0.025ø | Otros 2 | 0.0001016 | 1 | 25 mmø
1009802 | Nivel 1 | 3.82957 | 0.025 | 3.98218 | 0.0004908 | 0.31276 | 3.84207 | 3.82957 | 3.84207 | 3.85457 | 3.84207 | Nivel 1 | 0 | 3.82957 | 3.84207 | 3.85457 | 0.025ø | Otros 2 | 0.0001016 | 1 | 25 mmø
1009889 | Nivel 1 | -0.4525 | 0.025 | 4.75238 | 0.0004908 | 0.373251 | -0.44 | -0.4525 | -0.44 | -0.4275 | -0.44 | Nivel 1 | 0 | -0.4525 | -0.44 | -0.4275 | 0.025ø | Otros 2 | 0.0001016 | 3 | 25 mmø
1009899 | Nivel 1 | -0.549341 | 0.025 | 0.088703 | 0.0004908 | 0.00696672 | -0.460638 | -0.549341 | -0.549341 | -0.549341 | -0.549341 | Nivel 1 |  | -0.460637 | -0.460638 | -0.460637 | 0.025ø | Otros 2 | 0.0001016 | 3 | 25 mmø
1009927 | Nivel 1 | -0.4525 | 0.025 | 3.20341 | 0.0004908 | 0.251596 | -0.44 | -0.4525 | -0.44 | -0.4275 | -0.44 | Nivel 1 | 0 | -0.4525 | -0.44 | -0.4275 | 0.025ø | Otros 2 | 0.0001016 | 2 | 25 mmø

# IfcPipeSegment: Pipe Types:Norma, Pipe Types:Norma:1008690
In: Nivel 1
Type - Other - Category: Pipes; Family Name: Pipe Types
Type - Identity Data - Type Name: Norma
Classification: D20 (FEMAP58); Material: Cobre; Group: Otros 1
Pset_EnvironmentalImpactIndicators - Reference: Pipe Types:Norma; sets with these values: 2
Pset_PipeSegmentOccurrence - InvertElevation: 2.99 m
Pset_FlowSegmentDiameter - Diameter: 0.02 m
Qto_PipeSegmentBaseQuantities - Length: 4.78012 m; GrossCrossSectionArea: 0.000314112 m2; NetCrossSectionArea: 0.000314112 m2; OuterSurfaceArea: 0.300344 m2
Other - Family: Pipe Types; Type: Norma; Family and Type: Pipe Types: Norma; Type Id: 142438
Constraints - Horizontal Justification: Center; Reference Level: Nivel 1; Slope: 0; Vertical Justification: Middle; End Middle Elevation: 3 m; Lower End Bottom Elevation: 2.99 m; Lower End Centerline Elevation: 3 m; Lower End Invert Elevation: 2.99 m; Lower End Obvert Elevation: 3.01 m; Lower End Top Elevation: 3.01 m; Middle Elevation: 3 m; Start Middle Elevation: 3 m; Upper End Bottom Elevation: 2.99 m; Upper End Centerline Elevation: 3 m; Upper End Invert Elevation: 2.99 m; Upper End Obvert Elevation: 3.01 m; Upper End Top Elevation: 3.01 m
Dimensions - Wall Thickness: 0 m; Inside Diameter: 0.02 m; Length: 4.78012 m; Outside Diameter: 0.02 m; Size: 0.020ø
Mechanical - Material: Cobre; Pipe Segment: Cobre - A; Schedule/Type: A; System Type: Otros; Area: 0.300344 m2; Connection Type: Generic; Diameter: 0.02 m; Invert Elevation: 2.99 m; Roughness: 0.00000254 m; System Classification: Other; System Name: Otros 1
Mechanical - Flow - Relative Roughness: 0.000127; Section: 31
Phasing - Phase Created: Nueva construcción
Insulation - Insulation Thickness: 0 m; Lower End Bottom of Insulation Elevation: 2.99 m; Lower End Top of Insulation Elevation: 3.01 m; Overall Size: 20 mmø; Upper End Bottom of Insulation Elevation: 2.99 m; Upper End Top of Insulation Elevation: 3.01 m
AboveGround - AboveGround: yes

# IfcSlab: Floor:Genérico 300 mm, Floor:Genérico 300 mm:1003462
In: Nivel 1
Type - PredefinedType: FLOOR; Material: Suelo por defecto
Type - Other - Category: Floors; Family Name: Floor
Type - Construction - Default Thickness: 0.3 m; Function: Interior
Type - Graphics - Coarse Scale Fill Color: 0
Type - Identity Data - Type Name: Genérico 300 mm
Type - Analytical Properties - Absorptance: 0.7; Roughness: 3
Classification: C (FEMAP58)
Pset_EnvironmentalImpactIndicators - Reference: Floor:Genérico 300 mm; sets with these values: 2
Pset_SlabCommon - IsExternal: no; Reference: Floor:Genérico 300 mm; PitchAngle: 0 deg; LoadBearing: no
Qto_SlabBaseQuantities - Width: 8.08009 m; Length: 1.55 m; Depth: 0.3 m; Perimeter: 63.1896 m; GrossArea: 12.5241 m2; NetArea: 12.5241 m2; GrossVolume: 3.75724 m3; NetVolume: 3.75724 m3
Other - Family: Floor; Family and Type: Floor: Genérico 300 mm; Type: Genérico 300 mm; Type Id: 759
Constraints - Level: Nivel 1; Height Offset From Level: 0 m; Related to Mass: no; Room Bounding: yes
Dimensions - Area: 12.5241 m2; Elevation at Bottom: -0.3 m; Elevation at Bottom Core: -0.3 m; Elevation at Top: 0 m; Elevation at Top Core: 0 m; Perimeter: 19.2602 m; Thickness: 0.3 m; Volume: 3.75724 m3
Phasing - Phase Created: Nueva construcción
Structural - Structural: no
AboveGround - AboveGround: yes

# IfcTank: Estanque:Estanque (2)
In: Nivel 1
Type - PredefinedType: PRESSUREVESSEL; Material: <Unnamed>
Type - Other - Category: Mechanical Equipment; Family Name: Estanque
Type - Constraints - Default Elevation: 0 m
Type - Dimensions - Largo: 3.6 m; Radio: 0.6 m; Salida: 0.025 m
Type - Identity Data - Type Name: Estanque
Classification: D (FEMAP58); Group: Otros 2
Pset_BuildingElementProxyCommon - IsExternal: no; Reference: Estanque:Estanque
Pset_EnvironmentalImpactIndicators - Reference: Estanque:Estanque
Qto_BuildingElementProxyQuantities - NetSurfaceArea: 14.0436 m2; NetVolume: 2.06181 m3
Other - Family: Estanque; Family and Type: Estanque: Estanque; Type: Estanque; Type Id: 1001584
Constraints - Level: Nivel 1; Elevation from Level: -1 m; Host: Level : Nivel 1; Offset from Host: -1 m
Dimensions - Area: 7.02181 m2; Volume: 2.06181 m3
Mechanical - System Classification: Undefined,Other; System Name: Otros 2
Phasing - Phase Created: Nueva construcción
AboveGround - AboveGround: yes
Name (Estanque:Estanque:...)
1001599
1008885 | Identity Data - Mark: 16

# IfcTank: Gas_Cylinder_18019:Gas_Cylinder_18019 (2)
In: Nivel 1
Type - PredefinedType: PRESSUREVESSEL; Material: <Unnamed>, Valve
Type - Other - Category: Mechanical Equipment; Family Name: Gas_Cylinder_18019; Tank Fill Height: 1.2 m
Type - Constraints - Default Elevation: 13.1234 m
Type - Dimensions - Salida: 0.013 m
Type - Identity Data - Type Name: Gas_Cylinder_18019
Classification: D (FEMAP58); Group: Otros 1
Pset_BuildingElementProxyCommon - IsExternal: no; Reference: Gas_Cylinder_18019:Gas_Cylinder_18019
Pset_EnvironmentalImpactIndicators - Reference: Gas_Cylinder_18019:Gas_Cylinder_18019
Qto_BuildingElementProxyQuantities - NetSurfaceArea: 3.77923 m2; NetVolume: 0.457277 m3
Other - Family: Gas_Cylinder_18019; Family and Type: Gas_Cylinder_18019: Gas_Cylinder_18019; Type: Gas_Cylinder_18019; Type Id: 1003419
Constraints - Elevation from Level: 0 m; Level: Nivel 1; Offset from Host: 0 m; Schedule Level: Nivel 1; Work Plane: Floor : Genérico 300 mm
Dimensions - Area: 1.88962 m2; Volume: 0.457277 m3
Identity Data - Comments: GAS
Mechanical - System Classification: Other; System Name: Otros 1
Phasing - Phase Created: Nueva construcción
AboveGround - AboveGround: yes
Name (Gas_Cylinder_18019:Gas_Cylinder_18019:...)
1003499
1004430 | Identity Data - Mark: 11

# IfcTank: M_Vaso de expansión - Independiente - Vertical:452 L, M_Vaso de expansión - Independiente - Vertical:452 L:996003
In: Nivel 1
Type - PredefinedType: EXPANSION; Material: <Unnamed>
Type - Other - Category: Mechanical Equipment; Altura 1: 0.06 m; Altura 2: 1.349 m; Altura 3: 0.105 m; Diámetro 1: 0.492 m; Diámetro 2: 0.533 m; Family Name: M_Vaso de expansión - Independiente - Vertical; Radio_1: 0.246 m; Radio 2: 0.2665 m; Radio de depósito: 0.33 m
Type - Constraints - Default Elevation: 0 m
Type - Dimensions - Altura de depósito: 1.47 m; Diámetro de depósito: 0.66 m; Diámetro nominal: 0.025 m; Radio nominal: 0.0125 m
Type - Identity Data - OmniClass Number: 23.75.70.11.14; OmniClass Title: Expansion Vessels; Type Name: 452 L
Classification: D (FEMAP58)
Pset_BuildingElementProxyCommon - Reference: M_Vaso de expansión - Independiente - Vertical:452 L; IsExternal: no
Pset_EnvironmentalImpactIndicators - Reference: M_Vaso de expansión - Independiente - Vertical:452 L
Qto_BuildingElementProxyQuantities - NetSurfaceArea: 3.6739 m2; NetVolume: 0.497357 m3
Other - Family: M_Vaso de expansión - Independiente - Vertical; Family and Type: M_Vaso de expansión - Independiente - Vertical: 452 L; Type: 452 L; Type Id: 995988
Constraints - Elevation from Level: 0 m; Host: Level : Nivel 1; Level: Nivel 1; Offset from Host: 0 m
Dimensions - Area: 1.83695 m2; Volume: 0.497357 m3
Identity Data - Mark: 9
Mechanical - Flujo: 0.06 dm3/s; Pérdida de carga: 0 Pa; System Classification: Undefined
Phasing - Phase Created: Nueva construcción
AboveGround - AboveGround: yes
